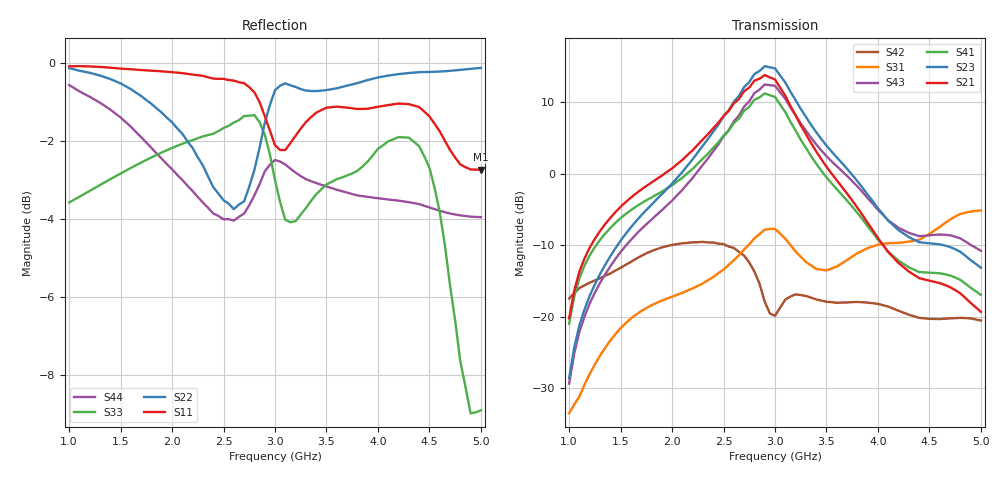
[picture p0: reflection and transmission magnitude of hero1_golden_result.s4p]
# HZ S RI R 50
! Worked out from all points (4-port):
!   81 points, 1 GHz to 5 GHz, reference 50 ohm
!   strongest paths, dB at 1 GHz, 2 GHz, 3 GHz, 4 GHz, 5 GHz:
!     S21: -20.2, 0.7, 13.1, -9.0, -19.3
!     S23: -28.6, -1.4, 14.7, -4.9, -13.1
!     S41: -21.0, -1.7, 10.7, -9.2, -16.9
!     S43: -29.4, -3.8, 12.3, -5.1, -10.8
!     S31: -33.5, -17.2, -7.7, -9.9, -5.1
!     S42: -17.5, -10.0, -19.9, -18.2, -20.5
!   lowest |S11| = -2.7 dB at 5 GHz (marker M1), VSWR 6.42, Z = 40.5 + j95.8 ohm
!   |S11| at or under -10 dB: nowhere
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1e9  -0.6607 0.7389  0.00128 0.000883  -0.0125 0.0171  0.00111 0.000888
     -0.0171 0.096  -0.6338 0.7555  -0.0364 -0.00771  0.0983 0.091
     -0.0125 0.0171  -0.000353 0.000478  0.3945 -0.5331  -0.000353 0.000414
     -0.0217 0.0865  0.0983 0.091  -0.0328 -0.00937  -0.7911 0.504
2.5e9  0.2389 0.9251  0.00178 0.00386  0.0637 0.2037  -0.00036 0.00307
       1.552 -1.997  0.617 0.2545  1.897 1.625  0.0911 -0.3086
       0.0637 0.2037  -0.00389 0.00158  -0.3567 -0.7453  -0.00302 -0.0005
       1.722 -0.6488  0.0911 -0.3086  0.5593 1.73  -0.2824 0.5642
2.8e9  0.4165 0.8182  0.00276 0.0036  0.1756 0.307  -0.000149 0.00333
       -2.334 -3.798  0.7072 0.1816  4.343 -2.394  -0.0593 -0.1982
       0.1756 0.307  -0.00414 0.00287  -0.5936 -0.6199  -0.0037 -0.000341
       0.4815 -3.248  -0.0593 -0.1982  3.584 0.7062  -0.3152 0.5995
2.95e9  0.4168 0.7064  0.00172 0.00575  0.309 0.2708  -0.00208 0.00399
        -4.673 -0.5244  0.882 0.0532  0.8738 -5.455  -0.0104 -0.105
        0.309 0.2708  -0.00685 0.0017  -0.6196 -0.4478  -0.00457 -0.00267
        -2.237 -2.724  -0.0104 -0.105  3.321 -2.475  -0.288 0.683
3.1e9  0.3323 0.6993  0.00456 0.00682  0.3288 0.1223  -0.00158 0.00611
       -2.349 2.597  0.9214 -0.1991  -3.074 -3.054  0.0479 -0.1227
       0.3288 0.1223  -0.0087 0.00524  -0.4938 -0.391  -0.00746 -0.00231
       -2.691 -0.0184  0.0479 -0.1227  0.178 -3.326  -0.2055 0.713
3.4e9  0.3567 0.7875  0.00607 0.00188  0.2111 0.0452  0.00154 0.00499
       0.6147 1.291  0.7885 -0.4766  -1.796 0.7566  -0.00109 -0.1322
       0.2111 0.0452  -0.00294 0.00815  -0.4692 -0.4913  -0.00689 0.00178
       -0.5908 1.015  -0.00109 -0.1322  -1.345 -0.8675  -0.142 0.6878
5e9  0.4787 0.5517  0.0148 -0.00694  0.4804 -0.2744  0.0129 0.0171
     -0.0108 -0.1077  -0.0513 -0.9853  0.2197 -0.0134  -0.0378 -0.0861
     0.4804 -0.2744  0.0129 0.0305  -0.1284 0.3353  -0.0357 0.025
     0.1355 -0.0432  -0.0378 -0.0861  0.0772 0.2786  0.1422 0.6189
